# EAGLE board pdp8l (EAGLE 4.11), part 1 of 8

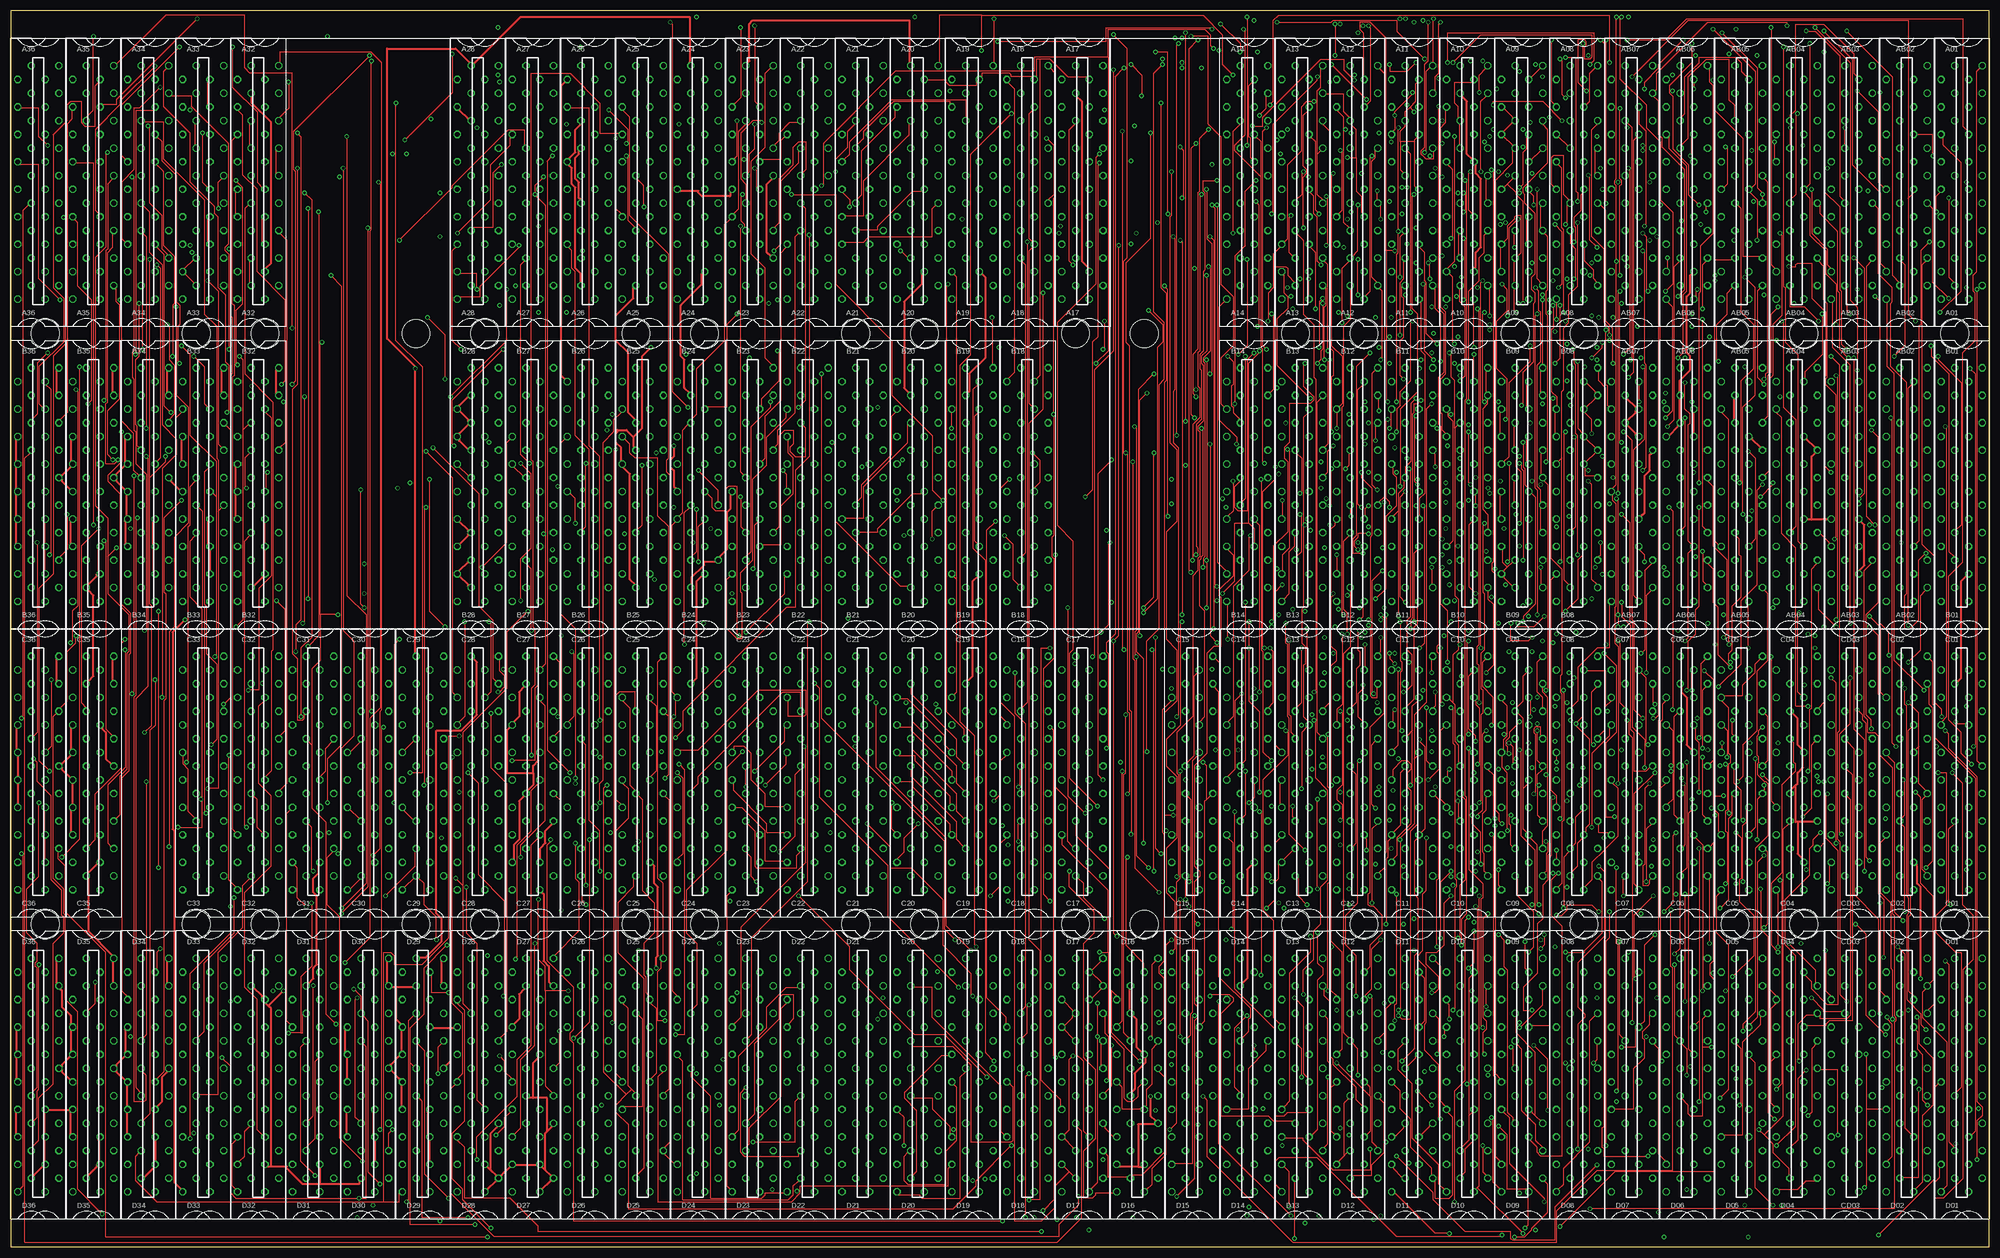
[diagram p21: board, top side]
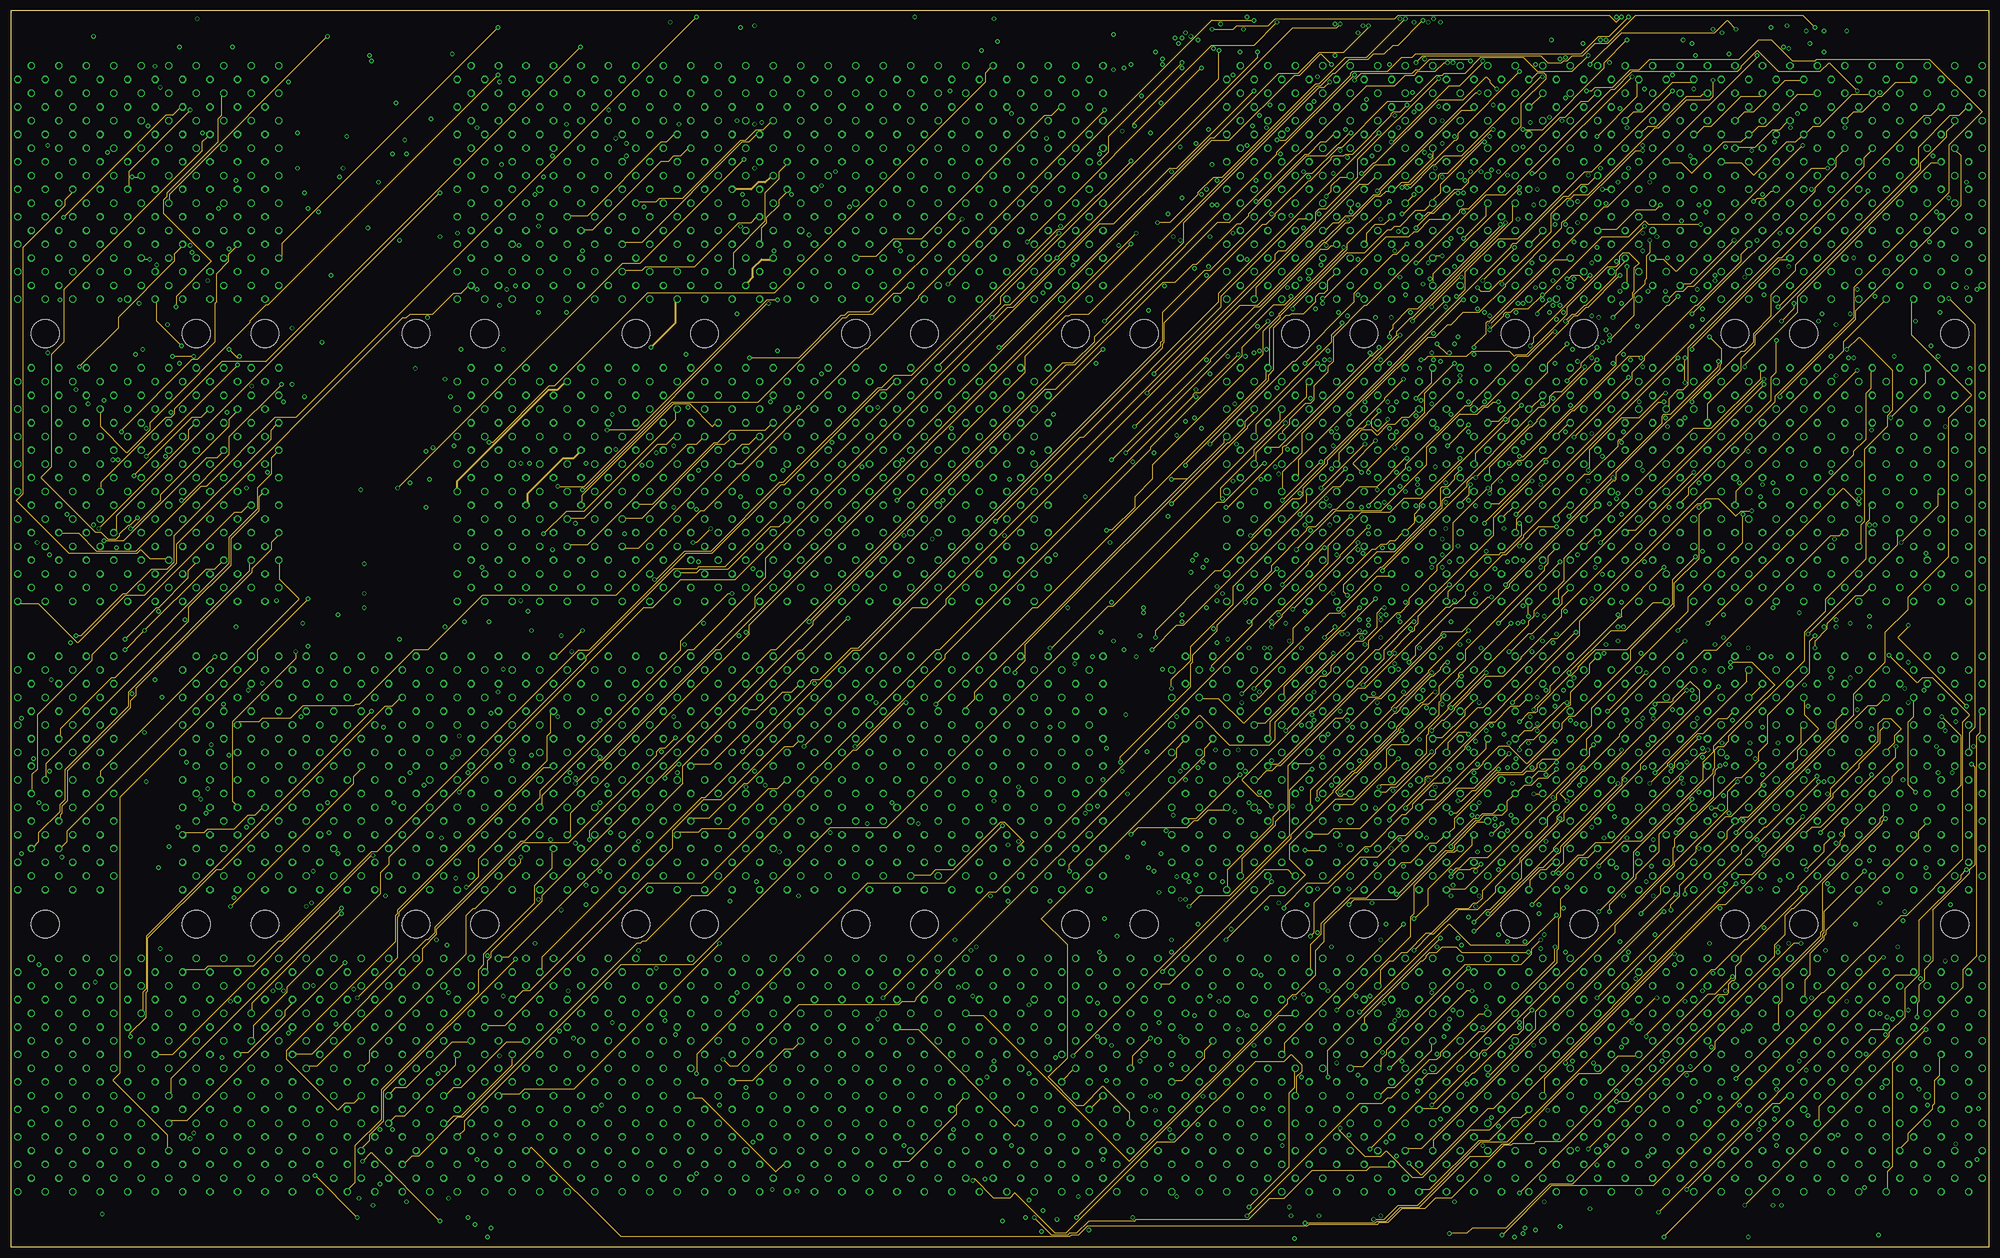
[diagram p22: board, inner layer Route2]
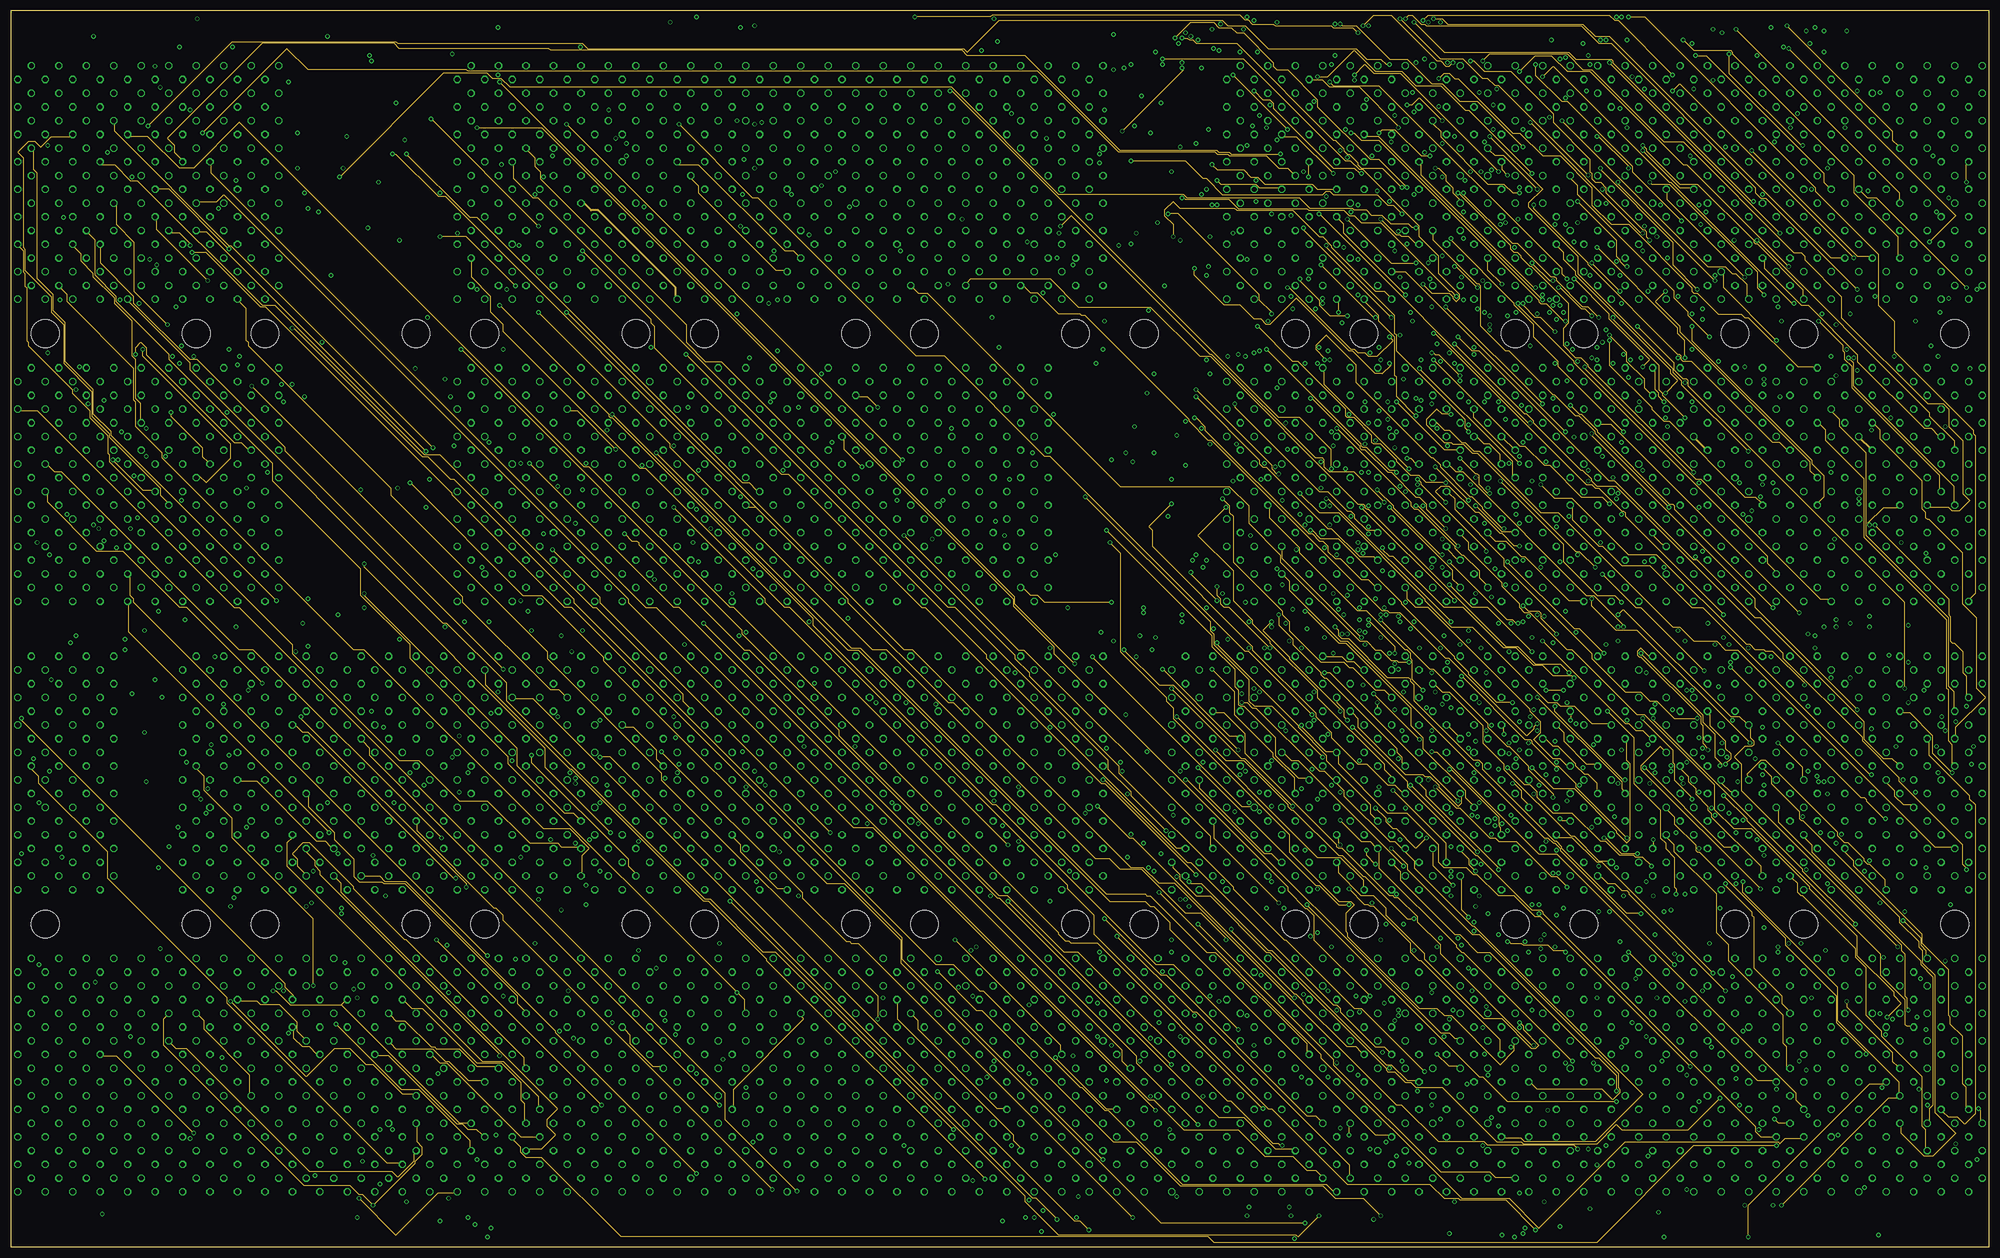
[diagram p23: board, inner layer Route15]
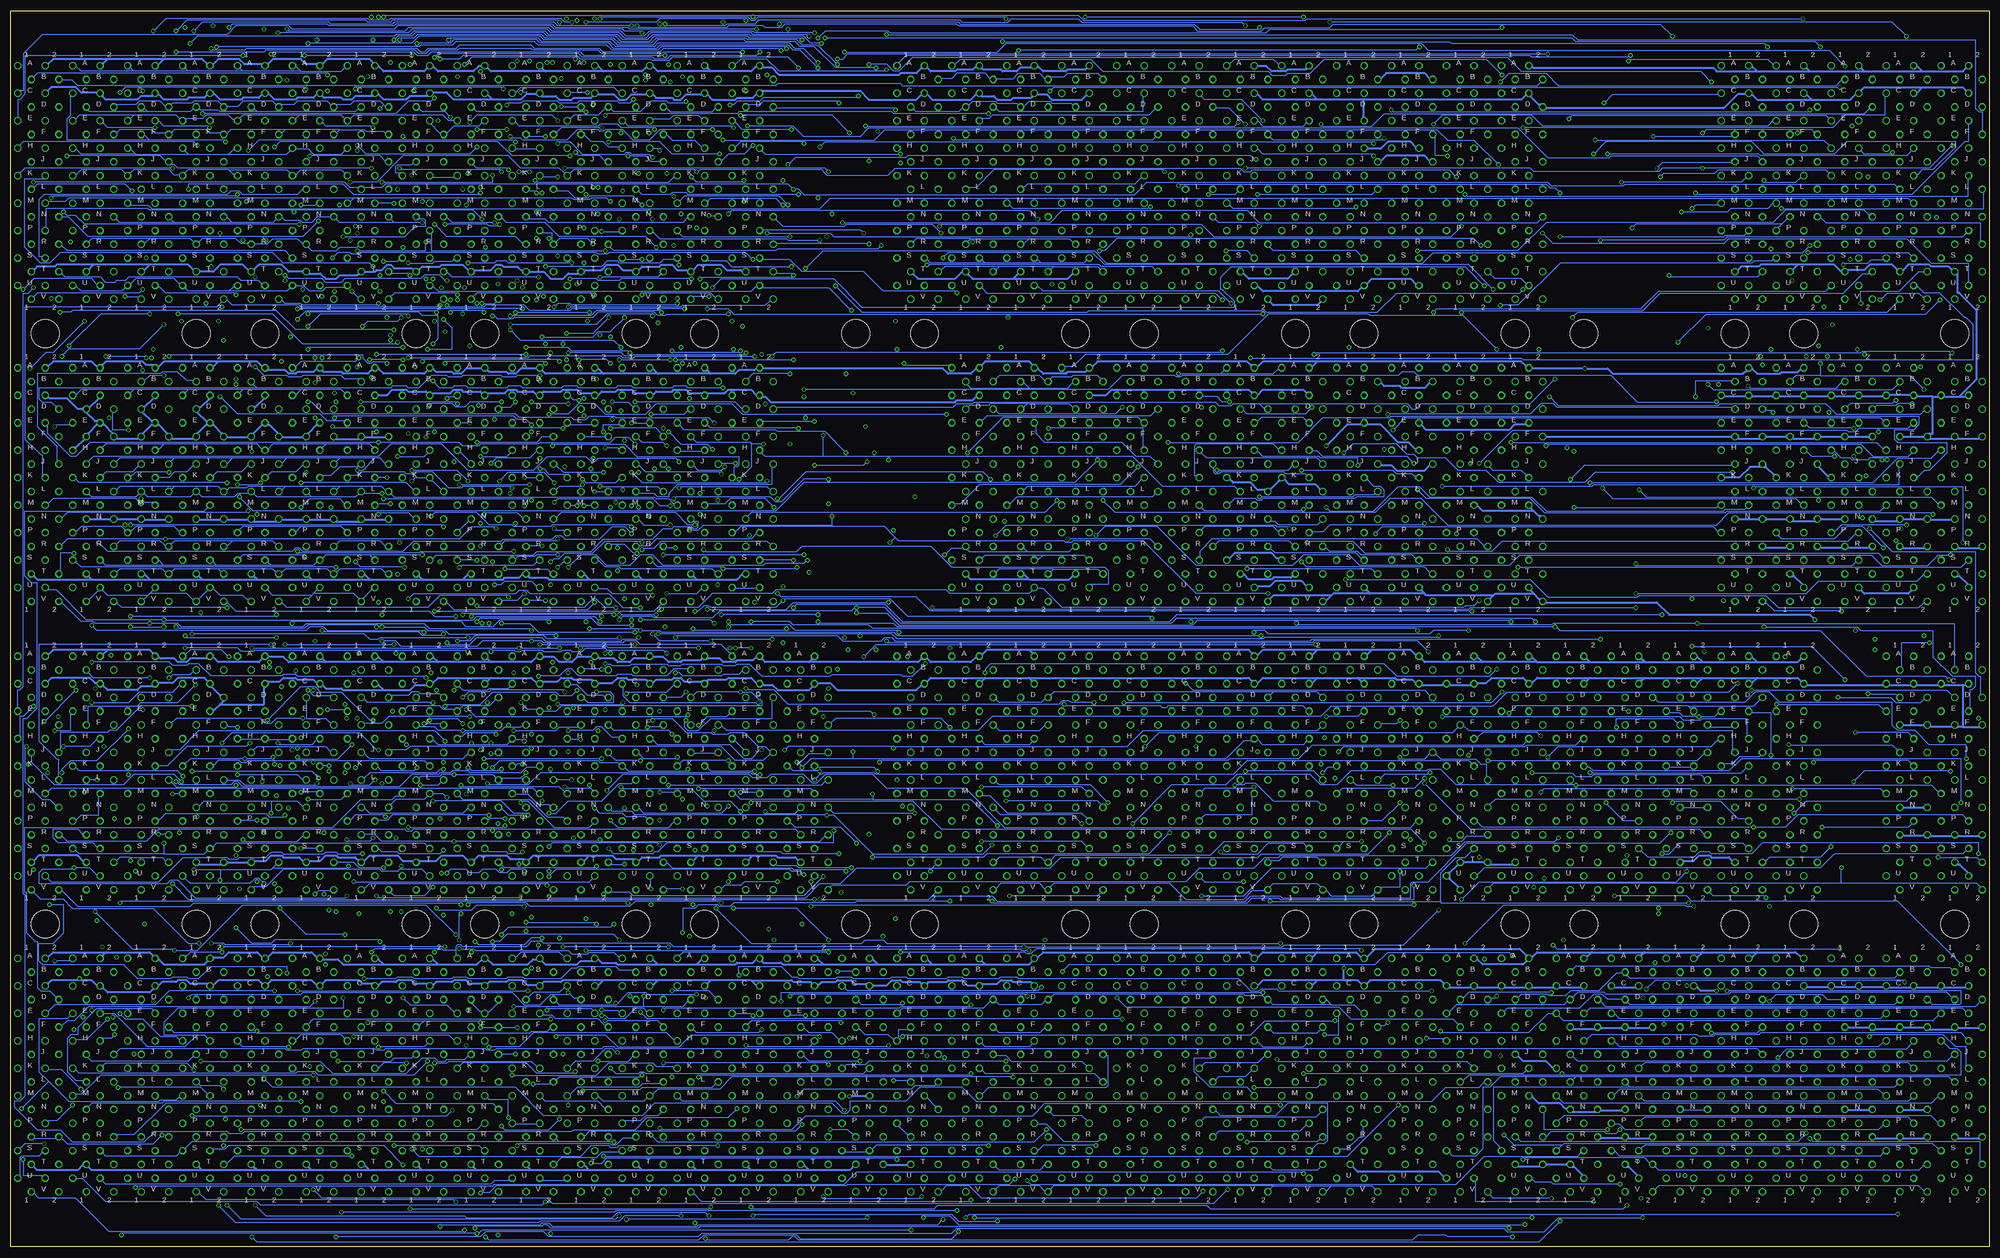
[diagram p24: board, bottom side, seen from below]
Size 457.2 x 285.75 mm. Coordinates in mm from the lower left corner, seen from the top.
Outline: 0,0 457.2,0 457.2,285.75 0,285.75 0,0
Copper layers (1*2*15*16): Top 0.035mm / dielectric 1.5mm / Route2 0.035mm / dielectric 0.15mm / Route15 0.035mm / dielectric 0.2mm / Bottom 0.035mm
Design rules "10mils": minimum track width 8mil, minimum drill 24mil, track to track 8mil, track to pad 8mil, pad to pad 8mil, via to via 8mil, smd to smd 8mil, copper to edge 25mil, drill to drill 8mil, minimum pad ring 8mil, minimum via ring 8mil, stop-mask expansion 0mil, vias tented up to drill 0mil, thermal gap 10mil
Net classes: 1 Supply: width 0.508 mm

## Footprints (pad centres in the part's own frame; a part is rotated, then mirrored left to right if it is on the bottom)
H807 = drill 1.092 octagon: A1 4.763,28.575; A2 -1.587,28.575; B1 1.587,25.4; B2 -4.763,25.4; C1 4.763,22.225; C2 -1.587,22.225; D1 1.587,19.05; D2 -4.763,19.05; E1 4.763,15.875; E2 -1.587,15.875; F1 1.587,12.7; F2 -4.763,12.7; H1 4.763,9.525; H2 -1.587,9.525; J1 1.587,6.35; J2 -4.763,6.35; K1 4.763,3.175; K2 -1.587,3.175; L1 1.587,0; L2 -4.763,0; M1 4.763,-3.175; M2 -1.587,-3.175; N1 1.587,-6.35; N2 -4.763,-6.35; P1 4.763,-9.525; P2 -1.587,-9.525; R1 1.587,-12.7; R2 -4.763,-12.7; S1 4.763,-15.875; S2 -1.587,-15.875; T1 1.587,-19.05; T2 -4.763,-19.05; U1 4.763,-22.225; U2 -1.587,-22.225; V1 1.587,-25.4; V2 -4.763,-25.4
H807-2 = drill 1.092 octagon: AA1 4.763,60.325; AA2 -1.587,60.325; AB1 1.587,57.15; AB2 -4.763,57.15; AC1 4.763,53.975; AC2 -1.587,53.975; AD1 1.587,50.8; AD2 -4.763,50.8; AE1 4.763,47.625; AE2 -1.587,47.625; AF1 1.587,44.45; AF2 -4.763,44.45; AH1 4.763,41.275; AH2 -1.587,41.275; AJ1 1.587,38.1; AJ2 -4.763,38.1; AK1 4.763,34.925; AK2 -1.587,34.925; AL1 1.587,31.75; AL2 -4.763,31.75; AM1 4.763,28.575; AM2 -1.587,28.575; AN1 1.587,25.4; AN2 -4.763,25.4; AP1 4.763,22.225; AP2 -1.587,22.225; AR1 1.587,19.05; AR2 -4.763,19.05; AS1 4.763,15.875; AS2 -1.587,15.875; AT1 1.587,12.7; AT2 -4.763,12.7; AU1 4.763,9.525; AU2 -1.587,9.525; AV1 1.587,6.35; AV2 -4.763,6.35; BA1 4.763,-9.525; BA2 -1.587,-9.525; BB1 1.587,-12.7; BB2 -4.763,-12.7; BC1 4.763,-15.875; BC2 -1.587,-15.875; BD1 1.587,-19.05; BD2 -4.763,-19.05; BE1 4.763,-22.225; BE2 -1.587,-22.225; BF1 1.587,-25.4; BF2 -4.763,-25.4; BH1 4.763,-28.575; BH2 -1.587,-28.575; BJ1 1.587,-31.75; BJ2 -4.763,-31.75; BK1 4.763,-34.925; BK2 -1.587,-34.925; BL1 1.587,-38.1; BL2 -4.763,-38.1; BM1 4.763,-41.275; BM2 -1.587,-41.275; BN1 1.587,-44.45; BN2 -4.763,-44.45; BP1 4.763,-47.625; BP2 -1.587,-47.625; BR1 1.587,-50.8; BR2 -4.763,-50.8; BS1 4.763,-53.975; BS2 -1.587,-53.975; BT1 1.587,-57.15; BT2 -4.763,-57.15; BU1 4.763,-60.325; BU2 -1.587,-60.325; BV1 1.587,-63.5; BV2 -4.763,-63.5
CBLOCK = hole 6.452: 7.938,68.263; 42.862,68.263

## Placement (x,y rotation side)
A01  G921  [H807]  450.85,244.47 0 top
A08  M617  [H807]  361.95,244.47 0 top
A09  M617  [H807]  349.25,244.47 0 top
A10  M160  [H807]  336.55,244.47 0 top
A11  M115  [H807]  323.85,244.47 0 top
A12  M160  [H807]  311.15,244.47 0 top
A13  M160  [H807]  298.45,244.47 0 top
A14  M115  [H807]  285.75,244.47 0 top
A17  G020  [H807]  247.65,244.47 0 top
A18  G020  [H807]  234.95,244.47 0 top
A19  G020  [H807]  222.25,244.47 0 top
A20  G020  [H807]  209.55,244.47 0 top
A21  W025A  [H807]  196.85,244.47 0 top
A22  W025A  [H807]  184.15,244.47 0 top
A23  G228  [H807]  171.45,244.47 0 top
A24  G228  [H807]  158.75,244.47 0 top
A25  G624  [H807]  146.05,244.47 0 top
A26  G624  [H807]  133.35,244.47 0 top
A27  G826A  [H807]  120.65,244.47 0 top
A28  G785A  [H807]  107.95,244.47 0 top
A32  M516  [H807]  57.15,244.47 0 top
A33  M516  [H807]  44.45,244.47 0 top
A34  M111  [H807]  31.75,244.47 0 top
A35  M111  [H807]  19.05,244.47 0 top
A36  M916  [H807]  6.35,244.47 0 top
AB02  M220  [H807-2]  438.15,212.72 0 top
AB03  M220  [H807-2]  425.45,212.72 0 top
AB04  M220  [H807-2]  412.75,212.72 0 top
AB05  M220  [H807-2]  400.05,212.72 0 top
AB06  M220  [H807-2]  387.35,212.72 0 top
AB07  M220  [H807-2]  374.65,212.72 0 top
B01  G921  [H807]  450.85,174.62 0 top
B08  M617  [H807]  361.95,174.62 0 top
B09  M617  [H807]  349.25,174.62 0 top
B10  M160  [H807]  336.55,174.62 0 top
B11  M216  [H807]  323.85,174.62 0 top
B12  M111  [H807]  311.15,174.62 0 top
B13  M113  [H807]  298.45,174.62 0 top
B14  M119  [H807]  285.75,174.62 0 top
B18  G020  [H807]  234.95,174.62 0 top
B19  G020  [H807]  222.25,174.62 0 top
B20  G020  [H807]  209.55,174.62 0 top
B21  W025B  [H807]  196.85,174.62 0 top
B22  W025B  [H807]  184.15,174.62 0 top
B23  G228  [H807]  171.45,174.62 0 top
B24  G228  [H807]  158.75,174.62 0 top
B25  G624  [H807]  146.05,174.62 0 top
B26  G624  [H807]  133.35,174.62 0 top
B27  G826B  [H807]  120.65,174.62 0 top
B28  G785B  [H807]  107.95,174.62 0 top
B32  M906  [H807]  57.15,174.62 0 top
B33  M906  [H807]  44.45,174.62 0 top
B34  M903  [H807]  31.75,174.62 0 top
B35  M903  [H807]  19.05,174.62 0 top
B36  M903  [H807]  6.35,174.62 0 top
C01  G921  [H807]  450.85,107.95 0 top
C02  M113  [H807]  438.15,107.95 0 top
C04  M216  [H807]  412.75,107.95 0 top
C05  M113  [H807]  400.05,107.95 0 top
C06  M216  [H807]  387.35,107.95 0 top
C07  M111  [H807]  374.65,107.95 0 top
C08  M216  [H807]  361.95,107.95 0 top
C09  M115  [H807]  349.25,107.95 0 top
C10  M119  [H807]  336.55,107.95 0 top
C11  M117  [H807]  323.85,107.95 0 top
C12  M115  [H807]  311.15,107.95 0 top
C13  M117  [H807]  298.45,107.95 0 top
C14  M113  [H807]  285.75,107.95 0 top
C15  M113  [H807]  273.05,107.95 0 top
C17  M360  [H807]  247.65,107.95 0 top
C18  G221  [H807]  234.95,107.95 0 top
C19  G221  [H807]  222.25,107.95 0 top
C20  G610A  [H807]  209.55,107.95 0 top
C21  H807  [H807]  196.85,107.95 0 top
C22  G610A  [H807]  184.15,107.95 0 top
C23  G221  [H807]  171.45,107.95 0 top
C24  G221  [H807]  158.75,107.95 0 top
C25  G228  [H807]  146.05,107.95 0 top
C26  M002  [H807]  133.35,107.95 0 top
C27  M623  [H807]  120.65,107.95 0 top
C28  M115  [H807]  107.95,107.95 0 top
C29  M660  [H807]  95.25,107.95 0 top
C30  M660  [H807]  82.55,107.95 0 top
C31  M916  [H807]  69.85,107.95 0 top
C32  M916  [H807]  57.15,107.95 0 top
C33  W023  [H807]  44.45,107.95 0 top
C35  M903  [H807]  19.05,107.95 0 top
C36  M903  [H807]  6.35,107.95 0 top
CD03  M700  [H807-2]  425.45,76.2 0 top
D01  G921  [H807]  450.85,38.1 0 top
D02  M111  [H807]  438.15,38.1 0 top
D04  M115  [H807]  412.75,38.1 0 top
D05  M310  [H807]  400.05,38.1 0 top
D06  M310  [H807]  387.35,38.1 0 top
D07  M310  [H807]  374.65,38.1 0 top
D08  M310  [H807]  361.95,38.1 0 top
D09  M160  [H807]  349.25,38.1 0 top
D10  M216  [H807]  336.55,38.1 0 top
D11  M113  [H807]  323.85,38.1 0 top
D12  M113  [H807]  311.15,38.1 0 top
D13  M111  [H807]  298.45,38.1 0 top
D14  M310  [H807]  285.75,38.1 0 top
D15  M310  [H807]  273.05,38.1 0 top
D16  M216  [H807]  260.35,38.1 0 top
D17  M617  [H807]  247.65,38.1 0 top
D18  G221  [H807]  234.95,38.1 0 top
D19  G221  [H807]  222.25,38.1 0 top
D20  G611B  [H807]  209.55,38.1 0 top
D21  H807  [H807]  196.85,38.1 0 top
D22  G611B  [H807]  184.15,38.1 0 top
D23  G221  [H807]  171.45,38.1 0 top
D24  G221  [H807]  158.75,38.1 0 top
D25  G228  [H807]  146.05,38.1 0 top
D26  H807  [H807]  133.35,38.1 0 top
D27  M623  [H807]  120.65,38.1 0 top
D28  M623  [H807]  107.95,38.1 0 top
D29  M906  [H807]  95.25,38.1 0 top
D30  M906  [H807]  82.55,38.1 0 top
D31  M916  [H807]  69.85,38.1 0 top
D32  M916  [H807]  57.15,38.1 0 top
D33  W076  [H807]  44.45,38.1 0 top
D34  M903  [H807]  31.75,38.1 0 top
D35  M903  [H807]  19.05,38.1 0 top
D36  M903  [H807]  6.35,38.1 0 top
U$1  [CBLOCK]  0,6.35 0 top
U$2  [CBLOCK]  50.8,6.35 0 top
U$3  [CBLOCK]  101.6,6.35 0 top
U$4  [CBLOCK]  152.4,6.35 0 top
U$5  [CBLOCK]  203.2,6.35 0 top
U$6  [CBLOCK]  254,6.35 0 top
U$7  [CBLOCK]  304.8,6.35 0 top
U$8  [CBLOCK]  355.6,6.35 0 top
U$9  [CBLOCK]  406.4,6.35 0 top
U$10  [CBLOCK]  0,142.88 0 top
U$11  [CBLOCK]  50.8,142.88 0 top
U$12  [CBLOCK]  101.6,142.88 0 top
U$13  [CBLOCK]  152.4,142.88 0 top
U$14  [CBLOCK]  203.2,142.88 0 top
U$15  [CBLOCK]  254,142.88 0 top
U$16  [CBLOCK]  304.8,142.88 0 top
U$17  [CBLOCK]  355.6,142.88 0 top
U$18  [CBLOCK]  406.4,142.88 0 top

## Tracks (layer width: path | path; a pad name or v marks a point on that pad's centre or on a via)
3CYCLE  (via drill 0.61)
  Route15 0.203: v309.27,25.86 309.27,27.89 D12.P2 | v217.83,27.08 176.78,68.12 173.94,68.12 161.75,80.31 160.53,80.31 114.61,126.24 114.61,130.3 100.79,144.12 99.97,144.12 41.45,202.64 41.45,204.27 27.23,218.49 A34.V2
  Bottom 0.203: v309.27,25.86 307.64,24.23 220.68,24.23 v217.83,27.08
(IOT+OPR)\  (via drill 0.61)
  Top 0.203: v319.84,52.27 319.84,55.93 320.24,56.34 v320.24,81.53 | v340.97,119.33 340.16,118.52 340.16,101.04 338.94,99.82 v338.94,99.42
  Route2 0.203: v320.24,81.53 320.65,81.53 338.12,99.01 338.94,99.01 340.16,100.23 342.6,100.23 343.81,101.45 C09.N2
  Bottom 0.203: v319.84,52.27 307.64,52.27 306.83,51.46 D12.F2 | v340.97,119.33 331.22,119.33 330.4,120.14 325.93,120.14 C11.F1 | v338.94,99.42 339.34,99.82 342.19,99.82 343.81,101.45 C09.N2
+3V(1)  (via drill 0.61)
  Top 0.203: C02.U1 442.57,86.41 441.76,87.22 441.76,103.48 442.57,104.29 C02.M1 442.57,105.51 440.94,107.14 440.94,115.67 | v438.51,125.83 440.94,123.39 440.94,115.67 | 440.94,115.67 440.13,114.86 C02.J1
  Bottom 0.203: v438.51,125.83 429.97,125.83 427.53,128.27 419.81,128.27 418.19,129.9 C04.C1
+3V(2)  (via drill 0.61)
  Top 0.203: v383.64,111.2 384.05,111.61 384.05,119.33 383.24,120.14 C06.F2
  Route15 0.203: C05.U1 404.37,86.41 404.37,88.04 392.99,99.42 392.99,100.23 392.18,101.04 392.18,101.85 389.33,104.7 389.33,105.92 387.71,107.54 387.71,108.76 386.08,110.39 C06.K2
  Bottom 0.203: v383.64,111.2 385.27,111.2 C06.K2 | C06.D1 388.93,126.24 388.93,122.17 384.45,122.17 383.24,120.95 C06.F2
+3V(3)  (via drill 0.61)
  Top 0.203: C08.D1 363.32,126.24 363.32,122.58 v361.7,120.95 361.7,120.55 364.95,117.3 364.95,97.79 364.13,96.98 364.13,95.76 C08.R1 363.32,94.54 362.1,93.32 362.1,88.04 360.48,86.41 C08.U2
  Route15 0.203: C08.K1 366.17,111.61 364.13,111.61 358.85,116.89 358.85,118.92 357.63,120.14 C08.F2
  Bottom 0.203: v361.7,120.95 357.63,120.95 C08.F2 | C05.V1 401.12,83.16 398.27,83.16 394.21,87.22 371.86,87.22 371.45,86.82 367.79,86.82 367.39,87.22 362.1,87.22 360.88,86 C08.U2
+3V(4)
  Top 0.203: D11.L2 319.43,37.64 321.06,36.02 321.06,31.95 323.49,29.52 323.49,23.01 328.37,18.14 328.37,16.51 D11.U1 329.18,15.29 329.18,11.23 332.44,11.23 333.25,12.04 333.25,29.92 332.03,31.14 D10.N2 331.62,32.36 330.4,33.58 330.4,64.87 329.18,66.09 D11.A1 | D10.R1 338.12,24.64 336.09,22.61 336.09,17.32 335.28,16.51 D10.U2
  Bottom 0.203: D11.A1 329.18,66.9 330.4,68.12 339.34,68.12 340.56,66.9 D10.A1 | D10.U2 334.47,15.29 329.18,15.29 D11.U1
+3V(5)
  Top 0.203: C10.F2 331.22,120.14 330.4,119.33 330.4,103.48 331.62,102.26 C10.N2 | C10.U1 340.97,86.41 340.56,86.82 340.56,90.88 340.16,91.29 340.16,100.23 340.97,101.04 340.97,104.29 C10.M1
  Route15 0.203: C10.H2 334.47,118.11 332.44,120.14 C10.F2
  Bottom 0.203: C10.N2 332.44,101.85 332.84,102.26 335.28,102.26 337.72,104.7 340.56,104.7 C10.M1
+3V(6)  (via drill 0.61)
  Top 0.203: v352.75,244.5 352.75,223.77 353.57,222.96 A09.U1 | A10.H2 334.87,254.66 334.87,259.54 A10.E2 334.47,260.76 334.47,263.6 333.65,264.41 333.65,269.29 337.72,269.29 A10.B1
  Route15 0.203: v352.75,244.5 345.03,252.22 343,252.22 341.78,253.44 A10.H1
  Bottom 0.203: A10.H2 335.69,253.85 340.56,253.85 A10.H1
+3V(7)  (via drill 0.61)
  Top 0.203: B10.R2 332.44,162.41 333.25,163.22 333.25,190.86 332.03,192.07 332.03,192.89 B10.D2 | v353.57,157.12 353.57,153.06 B09.U1
  Route15 0.203: B10.S2 334.47,159.16 334.06,159.16 332.03,161.19 B10.R2
  Bottom 0.203: v353.57,157.12 353.16,157.53 336.5,157.53 335.69,158.34 B10.S2
+3V(8)
  Top 0.203: 352.35,30.33 351.54,31.14 351.54,31.55 D09.N1 | 352.35,30.33 353.57,29.11 D09.P1 | 352.35,30.33 352.35,44.96 347.88,49.43 347.88,53.49 D09.E2
  Route2 0.203: D11.V1 325.93,13.26 327.96,13.26 339.34,24.64 341.78,24.64 347.07,29.92 349.1,29.92 350.32,31.14 D09.N1
  Bottom 0.203: D09.D2 344.63,56.34 346.66,54.3 347.07,54.3 D09.E2 348.29,54.3 348.69,54.3 350.72,56.34 D09.D1
+3V(9)  (via drill 0.61)
  Top 0.203: v307.24,253.44 307.64,253.03 307.64,239.62 306.83,238.81 A12.N2
  Route15 0.203: v322.27,220.12 308.05,234.34 308.05,236.37 306.83,237.59 A12.N2
  Bottom 0.203: v307.24,253.44 307.64,253.85 308.86,253.85 A12.H2 | v322.27,220.12 322.68,220.52 349.5,220.52 350.32,219.71 A09.V1
+3V(10)  (via drill 0.61)
  Top 0.203: v364.54,177.04 365.35,176.22 365.35,154.28 366.57,153.06 B08.U1
  Bottom 0.203: v364.54,177.04 363.73,177.85 360.88,177.85 B08.K2 360.07,177.04 359.66,177.04 357.63,175.01 B08.L2
+3V(11)  (via drill 0.61)
  Top 0.203: 320.65,170.13 319.43,168.91 B11.N2 | 320.65,170.13 320.65,174.19 321.87,175.41 321.87,177.04 B11.K2 322.27,178.26 322.27,180.29 323.49,181.51 323.49,194.92 v324.71,196.14 | 320.65,170.13 v320.65,145.75
  Route2 0.203: v324.71,196.14 328.37,199.8 328.37,202.64 B11.A1 | v350.72,145.75 350.72,148.59 B09.V1
  Bottom 0.203: v350.72,145.75 350.32,146.15 321.06,146.15 v320.65,145.75
+3V(12)
  Top 0.203: B10.P1 341.38,165.66 341.38,169.32 340.16,170.54 340.16,193.7 341.38,194.92 341.38,196.14 B10.C1 340.97,197.36 340.97,202.64 B10.A1
  Route15 0.203: B08.V1 362.92,149.4 360.07,149.4 349.91,159.56 349.1,159.56 345.44,163.22 343,163.22 341.78,164.44 B10.P1
+3V(13)  (via drill 0.61)
  Top 0.203: v251.16,56.34 v251.16,48.62 251.16,14.88 249.53,13.26 D17.V1 | C25.A1 150.37,135.99 149.56,135.18 149.56,85.19 150.77,83.97 150.77,67.31 D25.A1 150.37,66.09 150.37,64.47 149.56,63.65 149.56,52.27 v151.18,52.27
  Bottom 0.203: v251.16,56.34 251.56,55.93 260.5,55.93 261.31,56.74 D16.D1 | v251.16,48.62 250.75,49.02 170.69,49.02 167.44,52.27 v151.18,52.27
+3V(15)
  Top 0.203: D31.S2 68.28,23.01 70.31,25.04 70.31,42.93 71.12,43.74 D31.J1 | C31.N2 64.62,101.04 63.8,100.23 63.8,52.27 64.62,51.46 D31.F2
  Route15 0.203: D31.F2 65.43,50.24 65.43,48.21 67.46,46.18 69.09,46.18 70.71,44.55 D31.J1
  Bottom 0.203: C31.N2 65.84,101.45 70.71,101.45 C31.N1
+3V(16)
  Top 0.203: D32.R1 58.12,25.86 56.9,27.08 56.9,57.15 54.05,60 54.05,81.94 60.15,88.04 60.15,104.29 57.3,107.14 57.3,125.02 58.52,126.24 C32.D1
+3V(17)
  Bottom 0.203: B14.U2 284.89,152.25 289.76,152.25 B14.U1
+3V(18)
  Top 0.203: A08.U1 366.57,222.96 365.76,223.77 365.76,225.81 363.73,227.84 363.73,231.09 A08.R1
-15V
  Top 0.203: A18.B2 230.43,269.29 232.05,267.67 232.05,202.23 230.43,200.61 B18.B2
  Route2 0.203: D33.B2 40.23,64.06 44.7,64.06 45.52,64.87 56.08,64.87 61.77,70.56 62.59,70.56 83.31,91.29 84.53,91.29 131.27,138.02 133.71,138.02 156.06,160.38 162.15,160.38 178,176.22 178.82,176.22 200.76,198.17 202.39,198.17 204.01,199.8 B20.B2
  Bottom 0.203: A20.B2 205.23,270.51 206.04,271.32 212.95,271.32 213.77,270.51 217.02,270.51 A19.B2 218.24,270.1 219.46,271.32 224.33,271.32 225.55,270.1 229.62,270.1 A18.B2 230.84,270.1 232.05,271.32 238.56,271.32 239.78,270.1 242.21,270.1 A17.B2 | B18.B2 229.62,200.61 228.8,201.42 219.46,201.42 218.24,200.2 B19.B2 217.02,200.61 216.61,201.02 212.14,201.02 211.73,201.42 206.04,201.42 205.23,200.61 B20.B2
A01B2
  Bottom 0.203: A28.B2 103.63,269.29 104.44,268.48 251.16,268.48 251.56,268.88 280.01,268.88 280.42,268.48 441.76,268.48 442.98,269.7 445.41,269.7 A01.B2
A01V1  (via drill 0.61)
  Route2 0.203: v264.97,236.78 267.82,236.78 274.32,243.28 274.32,243.69 277.98,247.34 280.01,247.34 301.55,268.88 302.36,268.88 308.46,274.98 313.33,274.98 v322.27,283.92
  Route15 0.203: v322.27,283.92 323.09,284.73 323.9,284.73 325.93,282.7 326.75,282.7 327.15,282.3 362.92,282.3 366.98,278.23 369.82,278.23 403.15,244.91 403.15,243.69 404.37,242.47 405.59,242.47 v426.72,221.34
  Bottom 0.203: v264.97,236.78 217.02,236.78 214.17,239.62 171.5,239.62 168.66,236.78 104.44,236.78 103.63,237.59 A28.N2 | v426.72,221.34 427.53,220.52 451.1,220.52 451.92,219.71 A01.V1
AC00  (via drill 0.61)
  Top 0.203: v130.45,93.32 130.45,85.19 131.27,84.38 131.27,73 125.58,67.31 D27.A1 | v286.11,102.67 287.32,103.89 287.32,107.14 C14.L1
  Route2 0.203: v382.02,195.33 380.8,195.33 372.26,186.79 371.86,186.79 371.45,186.38 371.45,185.17 364.95,178.66 363.73,178.66 349.5,164.44 349.5,164.03 345.44,159.97 344.63,159.97 336.09,151.44 336.09,150.62 334.06,148.59 333.25,148.59 332.44,147.78 331.62,147.78 312.93,129.08 311.3,129.08 293.42,111.2 292.61,111.2 291.39,109.98 290.17,109.98 288.14,107.95 C14.L1
  Route15 0.203: v382.02,195.33 380.8,196.54 380.8,197.36 379.98,198.17 379.98,202.64 AB07.BA1
  Bottom 0.203: v130.45,93.32 133.71,96.57 242.21,96.57 248.72,103.07 285.7,103.07 v286.11,102.67
AC00\  (via drill 0.61)
  Top 0.203: v301.95,204.27 302.77,205.08 302.77,207.11 303.17,207.52 v303.17,218.08 | v376.33,195.33 376.33,199.39 AB07.BB1
  Route2 0.203: v301.95,204.27 287.73,190.04 287.73,188.01 B14.F1 | v400.71,203.45 400.71,203.86 412.9,216.05 412.9,219.71 443.79,250.6 445.41,250.6 A01.J2
  Route15 0.203: v331.62,217.27 v353.97,194.92
  Bottom 0.203: v303.17,218.08 303.58,217.68 327.56,217.68 327.96,218.08 330.81,218.08 v331.62,217.27 | v353.97,194.92 354.38,195.33 v376.33,195.33 | v400.71,203.45 398.68,201.42 393.39,201.42 392.99,201.02 390.14,201.02 389.74,201.42 380.8,201.42 379.98,200.61 376.73,200.61 AB07.BB1
AC01  (via drill 0.61)
  Top 0.203: v377.14,234.34 377.95,233.53 377.95,221.34 v378.36,220.93
  Route2 0.203: v322.68,264.01 321.06,262.38 319.43,262.38 319.02,261.98 319.02,261.57 310.08,252.63 308.46,252.63 308.05,252.22 305.61,252.22 305.21,251.82 305.21,251.41 300.33,246.53 299.92,246.53 292.2,238.81 292.2,238.4 290.17,236.37 289.36,236.37 266.6,213.61 266.6,209.14 266.19,208.74 266.19,207.92 196.29,138.02 194.67,138.02 160.53,103.89 159.72,103.89 122.73,66.9 122.73,64.06 D27.B1
  Route15 0.203: v322.68,264.01 323.9,264.01 325.53,265.63 v330.81,260.35 | v351.13,259.94 376.73,234.34 v377.14,234.34
  Bottom 0.203: v330.81,260.35 332.03,261.57 349.5,261.57 v351.13,259.94 | v378.36,220.93 377.14,219.71 376.73,219.71 AB07.AV1
AC01\  (via drill 0.61)
  Top 0.203: v445.01,239.22 445.01,242.88 445.82,243.69 A01.L2
  Route2 0.203: v316.18,207.92 316.18,207.52 314.55,205.89 314.15,205.89 293.01,184.76 290.98,184.76 B14.H1 | v341.78,211.99 345.03,215.24 345.03,215.65 345.44,216.05 346.66,216.05 347.47,216.86 350.72,216.86 v353.97,220.12 354.38,220.12 367.79,233.53 373.89,233.53 377.55,237.19 378.36,236.37 v390.55,236.37
  Bottom 0.203: v316.18,207.92 317.81,209.55 339.34,209.55 v341.78,211.99 | v353.97,220.12 354.38,220.52 368.61,220.52 369.42,219.71 AB07.AV2 | v445.01,239.22 444.19,238.4 442.16,238.4 440.13,236.37 v390.55,236.37
AC02  (via drill 0.61)
  Route2 0.203: v201.57,57.56 225.96,81.94 227.58,81.94 292.61,146.96 293.42,146.96 304.39,157.94 304.39,162 312.12,169.72 318.62,169.72 321.87,172.97 325.93,172.97 334.87,181.91 v334.87,182.32 | v341.78,174.19 341.78,174.6 342.19,175.01 342.19,176.22 346.25,180.29 346.66,180.29 348.29,181.91 349.5,181.91 360.88,193.29 361.29,193.29 373.89,205.89 376.33,205.89 v376.73,205.49
  Route15 0.203: v334.87,182.32 338.53,178.66 338.94,178.66 339.34,178.26 339.34,176.22 341.38,174.19 v341.78,174.19
  Bottom 0.203: v201.57,57.56 199.54,55.52 150.37,55.52 147.52,52.68 123.95,52.68 122.73,51.46 D27.F1 | v376.73,205.49 377.55,204.67 390.14,204.67 391.36,203.45 AB06.BA1
AC02\  (via drill 0.61)
  Top 0.203: v388.52,195.33 388.52,199.39 AB06.BB1
  Route2 0.203: v294.64,190.45 287.73,183.54 287.73,181.51 B14.J1 | v429.16,244.09 429.16,243.69 412.5,227.03 412.5,225.81 406.81,220.12 406.81,215.24 402.74,211.18 402.74,209.14 400.71,207.11 399.9,207.11 388.52,195.73 v388.52,195.33
  Bottom 0.203: v294.64,190.45 295.86,191.67 317.4,191.67 317.81,192.07 323.49,192.07 324.31,191.26 327.15,191.26 327.56,191.67 339.75,191.67 340.56,192.48 384.86,192.48 387.71,195.33 v388.52,195.33 | v429.16,244.09 430.78,245.72 451.1,245.72 451.92,244.91 A01.L1
AC03  (via drill 0.61)
  Top 0.203: v130.05,48.21 133.71,51.87 v133.71,94.13 | v389.74,221.34 389.33,220.93 389.33,219.71 AB06.AV1
  Route2 0.203: v133.71,94.13 133.71,96.16 175.56,138.02 176.78,138.02 243.03,204.27 245.47,204.27 250.34,209.14 250.34,210.36 292.61,252.63 292.61,253.03 v310.49,270.92
  Route15 0.203: v310.49,270.92 312.93,273.36 314.96,271.32 321.06,271.32 v343.81,248.56 | v367.39,249.38 367.39,248.97 384.05,232.31 384.05,227.03 v389.74,221.34
  Bottom 0.203: v130.05,48.21 125.98,48.21 D27.H1 | v343.81,248.56 344.22,248.97 366.98,248.97 v367.39,249.38
AC03\  (via drill 0.61)
  Top 0.203: v382.42,191.67 384.05,193.29 384.05,217.27 382.83,218.49 AB06.AV2
  Route2 0.203: v332.03,185.17 v336.91,190.04 | v419.81,249.38 416.15,249.38 388.93,222.15 387.71,222.15 386.49,220.93 384.86,220.93 383.24,219.3 AB06.AV2
  Bottom 0.203: v332.03,185.17 331.62,185.57 315.37,185.57 312.52,182.73 288.95,182.73 288.95,180.7 289.36,180.29 290.17,180.29 290.17,178.26 B14.K1 | v336.91,190.04 338.12,191.26 340.16,191.26 340.97,192.07 382.02,192.07 v382.42,191.67 | v419.81,249.38 453.95,249.38 455.17,248.16 A01.K1
AC04  (via drill 0.61)
  Top 0.203: 123.55,59.18 123.55,64.87 121.92,66.5 v121.92,80.31 | 123.55,59.18 123.55,37.24 125.17,35.61 D27.M1 | v69.9,86.82 69.49,87.22 69.49,96.98 68.68,97.79 C31.P2 | v288.54,100.63 288.95,100.23 v288.95,62.84 | v128.83,59.18 123.55,59.18
  Route2 0.203: v316.18,106.32 316.59,106.73 319.84,106.73 327.15,114.05 327.15,118.11 327.56,118.52 327.56,119.74 332.03,124.21 332.03,125.02 350.72,143.71 350.72,144.53 351.94,145.75 351.94,146.96 358.85,153.87 358.85,159.16 388.93,189.23 392.99,189.23 404.37,200.61 404.37,202.64 AB05.BA1
  Bottom 0.203: v121.92,80.31 117.86,84.38 72.34,84.38 v69.9,86.82 | v316.18,106.32 315.77,105.92 299.92,105.92 297.08,103.07 290.98,103.07 v288.54,100.63 | v288.95,62.84 288.95,64.87 279.2,64.87 276.76,62.43 275.54,62.43 275.13,62.03 266.6,62.03 266.19,62.43 262.94,62.43 262.53,62.03 254,62.03 253.59,62.43 250.34,62.43 249.94,62.03 241,62.03 240.59,62.43 237.34,62.43 236.93,62.03 228.8,62.03 228.4,62.43 224.74,62.43 224.33,62.03 173.53,62.03 170.69,59.18 168.66,59.18 168.25,59.59 164.59,59.59 164.19,59.18 v128.83,59.18
AC04\  (via drill 0.61)
  Top 0.203: v287.32,206.7 285.7,205.08 285.7,170.13 283.67,170.13 282.85,170.94 282.85,175.82 284.07,177.04 B14.K2
  Route15 0.203: v328.37,206.7 328.78,206.7 329.18,206.3 330,206.3 v334.87,201.42
  Bottom 0.203: v287.32,206.7 287.73,206.3 313.33,206.3 313.74,205.89 315.37,205.89 316.18,206.7 v328.37,206.7 | v334.87,201.42 340.16,201.42 340.56,201.02 343.41,201.02 343.81,201.42 352.75,201.42 353.16,201.02 356.01,201.02 356.41,201.42 360.07,201.42 362.92,198.58 365.35,198.58 365.76,198.98 369.01,198.98 369.42,198.58 400.3,198.58 | 400.3,198.58 401.12,199.39 AB05.BB1 | 400.3,198.58 450.7,198.58 450.7,196.14 449.88,195.33 447.85,195.33 446.63,194.11 B01.D2
AC05  (via drill 0.61)
  Top 0.203: v358.44,260.35 353.97,264.82 342.6,264.82 v342.6,264.01 | v305.21,273.36 v313.33,265.23
  Route2 0.203: v305.21,273.36 302.77,275.79 297.89,270.92 296.67,270.92 281.63,255.88 277.57,255.88 171.91,150.22 171.91,147.78 136.55,112.42 135.74,112.42 v130.45,107.14
  Route15 0.203: D27.N1 121.92,32.36 121.92,34.8 113.79,42.93 108.92,42.93 63.8,88.04 63.8,93.32 65.02,94.54 C31.R2 | v358.44,260.35 392.18,226.62 396.24,226.62 397.87,224.99 398.68,224.99 401.12,222.56 401.12,219.71 AB05.AV1
  Bottom 0.203: v342.6,264.01 342.19,264.41 339.34,264.41 338.94,264.82 330.81,264.82 330.4,264.41 326.34,264.41 325.93,264.82 316.99,264.82 316.59,264.41 314.15,264.41 v313.33,265.23 | v130.45,107.14 119.89,96.57 67.06,96.57 65.84,95.35 C31.R2
AC05\  (via drill 0.61)
  Top 0.203: v372.26,218.08 371.86,217.68 371.86,186.38 v372.26,185.98
  Route2 0.203: v312.93,185.57 v302.77,175.41
  Bottom 0.203: v302.77,175.41 302.36,175.82 282.45,175.82 281.63,175.01 B14.L2 | v312.93,185.57 314.55,187.2 317.4,187.2 318.62,185.98 334.87,185.98 335.28,185.57 348.69,185.57 349.1,185.17 352.75,185.17 353.57,185.98 v372.26,185.98 438.91,185.98 442.16,182.73 443.38,182.73 448.67,188.01 448.67,190.04 B01.E2 | v372.26,218.08 372.67,217.68 389.74,217.68 390.14,218.08 393.8,218.08 394.61,218.9 AB05.AV2
AC06  (via drill 0.61)
  Top 0.203: v105.66,109.58 108.1,107.14 108.1,86 114.2,79.91 114.2,58.37 v113.79,57.96
  Route2 0.203: v330,270.1 311.3,251.41 311.3,247.34 303.99,240.03 302.36,240.03 301.55,239.22 301.55,237.19 294.64,230.28 293.01,230.28 292.2,229.46 292.2,228.24 211.73,147.78 208.48,147.78 164.19,103.48 160.12,103.48 152.81,96.16 152.81,92.1 119.89,59.18 118.26,59.18 116.64,57.56 D27.D2
  Route15 0.203: v330,270.1 331.22,271.32 332.44,271.32 333.65,270.1 334.47,270.1 347.07,257.5 348.69,257.5 353.97,252.22 358.04,252.22 365.35,244.91 365.35,240.84 369.82,236.37 373.89,236.37 388.52,221.74 388.52,220.93 388.93,220.52 389.74,220.52 394.61,215.65 399.9,215.65 400.71,214.83 401.52,214.83 412.9,203.45 416.97,203.45 AB04.BA1
  Bottom 0.203: v105.66,109.58 96.32,109.58 95.5,108.76 91.85,108.76 91.44,109.17 66.65,109.17 65.84,108.36 C31.L2 | v113.79,57.96 114.2,57.56 115.42,57.56 D27.D2
AC06\  (via drill 0.61)
  Top 0.203: v285.29,205.89 285.29,172.97 284.48,172.16 B14.M2 | v365.35,205.49 367.79,207.92 v367.79,209.14 | v418.59,215.65 418.59,206.3 414.53,202.23 414.53,200.61 AB04.BB1
  Bottom 0.203: v285.29,205.89 312.93,205.89 313.33,205.49 315.77,205.49 316.18,205.89 337.31,205.89 337.72,205.49 v365.35,205.49 | v367.79,209.14 368.2,208.74 389.74,208.74 396.65,215.65 v418.59,215.65 | B01.J2 446.63,181.51 446.63,185.17 451.1,189.64 451.1,201.83 422.66,201.83 422.25,202.23 418.59,202.23 416.56,200.2 414.93,200.2 AB04.BB1
AC07  (via drill 0.61)
  Route2 0.203: v307.24,282.7 306.43,281.89 296.27,281.89 231.65,217.27 230.43,217.27 167.44,154.28 154.84,154.28 148.34,147.78 146.3,147.78 v103.63,105.1
  Route15 0.203: C31.M2 68.68,104.29 68.68,101.85 74.78,95.76 74.78,94.13 79.25,89.66 79.25,85.6 80.47,84.38 85.75,84.38 86.16,83.97 91.03,83.97 117.04,57.96 117.04,56.34 118.67,54.71 D27.E2 | v377.14,254.66 377.95,253.85 377.95,253.44 385.67,245.72 389.74,245.72 402.74,232.72 402.74,232.31 403.15,231.9 403.56,231.9 414.12,221.34 414.12,219.71 AB04.AV1 | v349.5,254.25 338.94,264.82 334.87,264.82 330.81,268.88 328.37,268.88 322.68,274.57 318.62,274.57 310.9,282.3 307.64,282.3 v307.24,282.7
  Bottom 0.203: v377.14,254.66 375.11,252.63 351.13,252.63 v349.5,254.25 | v103.63,105.1 102.82,105.92 69.09,105.92 68.68,105.51 C31.M2
AC07\  (via drill 0.61)
  Top 0.203: v282.45,177.04 282.45,170.13 281.23,168.91 B14.N2 | v356.82,204.27 358.04,205.49 v358.04,217.68
  Route2 0.203: v313.74,179.07 313.33,179.48 326.75,192.89 326.75,197.36 v333.65,204.27
  Bottom 0.203: v282.45,177.04 282.85,176.63 311.3,176.63 v313.74,179.07 | v333.65,204.27 334.06,204.67 356.41,204.67 v356.82,204.27 | v358.04,217.68 358.44,217.27 390.14,217.27 390.55,217.68 405.99,217.68 407.21,218.9 AB04.AV2 408.43,218.49 409.65,217.27 453.95,217.27 453.95,186.79 450.29,183.13 449.88,183.13 449.88,178.26 B01.K2
AC08  (via drill 0.61)
  Route2 0.203: v385.27,142.49 425.91,183.13 425.91,183.95 428.75,186.79 428.75,197.36 429.97,198.58 429.97,202.64 AB03.BA1 | v317.4,147.78 316.99,147.78 315.77,146.56 315.77,143.31 312.52,140.06 310.9,140.06 305.21,134.37 305.21,133.15 303.99,131.93 302.77,131.93 292.2,121.36 292.2,117.3 290.98,116.08 281.63,116.08 274.73,122.99 209.3,57.56 209.3,57.15 208.89,56.74 206.04,56.74 205.23,55.93 182.07,55.93 167.84,41.71 166.22,41.71 v164.59,43.33
  Route15 0.203: D27.K2 118.67,41.71 118.67,43.74 91.44,70.97 91.03,70.97 79.25,82.75 79.25,83.16 69.09,93.32 67.46,93.32 65.02,90.88 66.24,89.66 66.24,88.04 67.87,86.41 C31.U2 | v357.23,141.68 353.57,145.34 353.57,146.56 353.16,146.96 350.72,146.96 v349.5,148.18
  Bottom 0.203: v385.27,142.49 384.86,142.09 362.92,142.09 362.1,141.28 357.63,141.28 v357.23,141.68 | v349.5,148.18 349.1,147.78 324.71,147.78 322.68,149.81 321.87,149.81 319.84,147.78 v317.4,147.78 | v164.59,43.33 164.19,42.93 120.7,42.93 119.48,41.71 D27.K2
AC08\  (via drill 0.61)
  Top 0.203: v321.46,119.33 321.06,119.74 321.06,132.74 321.46,133.15 321.46,135.18 321.06,135.59 v321.06,144.53 | v421.84,201.42 422.25,201.02 422.25,145.34 v421.84,144.93
  Route2 0.203: v321.46,119.33 v307.24,105.1
  Bottom 0.203: v307.24,105.1 303.99,105.1 C13.M1 | v321.06,144.53 322.27,145.75 349.5,145.75 350.32,144.93 v421.84,144.93 439.73,144.93 446.63,151.84 448.67,151.84 B01.U2 | v421.84,201.42 425.09,201.42 426.31,200.2 AB03.BB1
AC09  (via drill 0.61)
  Top 0.203: v112.98,44.15 114.2,42.93 114.2,40.49 115.82,38.86 D27.L2 | v430.78,219.71 432,218.49 432,144.12 434.04,142.09 v434.04,136.8
  Route2 0.203: v434.04,136.8 440.54,130.3 441.76,131.52 444.19,131.52 452.73,122.99 451.1,121.36 451.1,89.66 438.1,76.66 436.88,76.66 419,58.78 418.59,58.78 v398.68,38.86
  Route15 0.203: v112.98,44.15 112.98,44.55 71.53,86 71.53,86.82 70.31,88.04 70.31,89.26 68.28,91.29 C31.S2
  Bottom 0.203: v430.78,219.71 427.53,219.71 AB03.AV1 | v398.68,38.86 396.65,36.83 340.56,36.83 334.06,30.33 311.3,30.33 308.46,33.17 267.41,33.17 264.97,30.73 264.16,30.73 263.35,31.55 263.35,33.58 250.34,33.58 247.09,36.83 237.34,36.83 234.09,33.58 128.83,33.58 125.58,36.83 117.86,36.83 116.64,38.05 D27.L2
AC09\  (via drill 0.61)
  Top 0.203: v425.09,144.12 425.09,203.86 421.03,207.92 421.03,218.49 AB03.AV2
  Route2 0.203: v336.91,142.49 327.56,133.15 327.56,132.74 322.27,127.46 321.87,127.46 319.02,124.61 319.02,124.21 300.33,105.51 300.33,102.26 C13.N1
  Bottom 0.203: v336.91,142.49 337.31,142.9 360.48,142.9 361.7,144.12 388.93,144.12 389.74,143.31 417.78,143.31 418.59,144.12 v425.09,144.12 437.69,144.12 438.1,144.53 440.94,144.53 445.41,149 B01.V2
AC10  (via drill 0.61)
  Top 0.203: v121.11,70.16 121.11,46.58 117.86,43.33 117.86,27.48 116.23,25.86 D27.R2 | v68.28,78.69 66.24,80.72 66.24,87.63 65.43,88.44 C31.T2 | v434.44,191.67 434.85,191.26 434.85,116.48 v435.66,115.67 | v418.19,95.76 416.56,94.13 416.56,92.91 415.75,92.1 415.75,86 410.06,80.31 410.06,69.75 412.5,67.31 412.5,27.89 v408.03,23.42
  Route2 0.203: v434.44,191.67 442.57,199.8 442.57,202.64 AB02.BA1 | v435.66,115.67 435.66,113.23 v418.19,95.76
  Route15 0.203: v408.03,23.42 388.93,23.42 366.57,1.07 277.98,1.07 276.76,2.29 141.02,2.29 122.73,20.57 119.08,20.57 117.86,21.79 117.86,23.01 116.23,24.64 D27.R2
  Bottom 0.203: v121.11,70.16 112.17,79.1 70.31,79.1 69.9,78.69 v68.28,78.69
AC10\  (via drill 0.61)
  Top 0.203: v438.51,143.71 438.51,198.58 439.32,199.39 AB02.BB1
  Route2 0.203: v318.62,98.6 318.62,99.01 326.75,107.14 326.75,108.36 327.15,108.76 328.37,108.76 v361.7,142.09 | v451.92,125.02 436.07,140.87 438.51,143.31 v438.51,143.71
  Bottom 0.203: v318.62,98.6 316.99,96.98 305.21,96.98 303.99,98.2 C13.P1 | v361.7,142.09 362.1,142.49 384.05,142.49 384.86,143.31 388.11,143.31 388.93,142.49 437.29,142.49 v438.51,143.71 | v451.92,125.02 454.36,122.58 455.17,122.58 455.17,118.11 C01.H1
AC11  (via drill 0.61)
  Top 0.203: v398.68,95.76 399.9,94.54 399.9,85.19 399.49,84.78 399.49,79.91 402.74,76.66 402.74,67.31 v397.87,62.43
  Route2 0.203: v398.68,95.76 425.91,122.99 425.91,127.86 433.22,135.18 433.22,142.09 438.51,147.37 438.51,150.22 447.85,159.56 447.85,191.67 453.14,196.95 439.32,210.77 439.32,218.49 AB02.AV1 | v397.87,62.43 393.8,58.37 392.18,58.37 358.04,24.23 352.35,24.23 351.94,23.83 347.07,23.83 346.66,23.42 345.03,23.42 332.84,11.23 329.18,11.23 326.75,8.79 321.46,8.79 318.21,5.54 316.18,5.54 315.77,5.13 299.92,5.13 299.52,4.72 248.72,4.72 246.69,2.69 245.06,2.69 244.65,2.29 141.02,2.29 120.29,23.01 119.48,22.2 D27.S2
  Route15 0.203: D27.S2 119.48,22.61 122.73,22.61 125.98,25.86 123.95,27.89 123.95,29.52 126.39,31.95 76.4,81.94 76.4,83.97 75.18,85.19 C31.U1
AC11\  (via drill 0.61)
  Top 0.203: v449.48,121.36 449.48,120.95 451.92,120.95 C01.F1 | v442.16,128.68 435.25,135.59 435.25,201.83 433.63,203.45 433.63,218.49 AB02.AV2
  Route2 0.203: C13.R1 300.74,95.35 304.39,95.35 305.61,96.57 311.71,96.57 329.18,114.05 329.18,114.86 338.94,124.61 340.16,124.61 356.01,140.46 357.23,140.46 400.71,183.95 400.71,184.35 423.47,207.11 423.47,209.14 432.82,218.49 AB02.AV2
  Bottom 0.203: v449.48,121.36 v442.16,128.68
AC\_ENABLE  (via drill 0.61)
  Top 0.203: v361.29,232.31 361.7,232.72 361.7,235.56 361.29,235.97 361.29,238 362.92,239.62 362.92,243.28 363.32,243.69 A08.L1 | v377.14,230.28 377.55,229.87 377.55,204.27 377.95,203.86 377.95,180.29 v377.14,179.48
  Bottom 0.203: 373.07,182.32 381.2,182.32 | 373.07,182.32 371.86,182.32 370.64,181.1 AB07.BJ2 | 381.2,182.32 382.02,181.51 AB06.BJ2 | v361.29,232.31 361.29,230.28 v377.14,230.28 | v377.14,179.48 375.92,179.48 373.07,182.32 | 393.39,182.32 394.61,181.1 AB05.BJ2 | 381.2,182.32 393.39,182.32 | 405.99,182.32 407.21,181.1 AB04.BJ2 | 393.39,182.32 405.99,182.32 | 419.4,182.32 420.22,181.51 AB03.BJ2 | 405.99,182.32 419.4,182.32 | 419.4,182.32 432,182.32 432.82,181.51 AB02.BJ2
AC_CLEAR  (via drill 0.61)
  Route15 0.203: v112.98,217.68 138.18,192.48 138.18,192.07 138.58,191.67 138.99,191.67 185.32,145.34 185.32,143.71 226.77,102.26 227.58,102.26 264.57,65.28 268.63,65.28 v283.67,50.24
  Bottom 0.203: v112.98,217.68 108.92,217.68 99.16,227.43 54.86,227.43 54.46,227.84 50.39,227.84 49.99,228.24 A33.S1 | v283.67,50.24 284.48,49.43 298.7,49.43 299.52,50.24 D13.F1
AC_CLEAR\  (via drill 0.61)
  Top 0.203: v346.66,46.18 347.07,45.77 347.07,41.71 D09.K2
  Bottom 0.203: v346.66,46.18 339.75,46.18 336.5,49.43 305.61,49.43 303.99,47.8 D13.H1
AC_ENABLE  (via drill 0.61)
  Top 0.203: v351.94,240.84 351.94,242.88 351.13,243.69 A09.L1
  Route15 0.203: v351.94,240.84 351.94,240.03 364.54,227.43 364.54,227.03 385.27,206.3 385.67,206.3 386.08,205.89 386.08,205.08 386.49,204.67 388.52,204.67 407.21,185.98 408.84,185.98 410.46,184.35 AB04.BH2
  Bottom 0.203: 384.45,185.57 374.29,185.57 373.48,184.76 AB07.BH2 | 384.45,185.57 385.27,184.76 AB06.BH2 | 384.45,185.57 396.65,185.57 397.87,184.35 AB05.BH2 399.08,184.35 400.3,185.57 412.5,185.57 | 421.84,185.57 423.06,184.35 AB03.BH2 | 412.5,185.57 421.84,185.57 | 412.5,185.57 411.68,184.76 AB04.BH2 | 421.84,185.57 435.25,185.57 436.07,184.76 AB02.BH2
AC_LOAD  (via drill 0.61)
  Top 0.203: v322.27,174.6 321.06,173.38 321.06,150.22 v322.27,149 | v405.18,199.39 403.56,201.02 403.56,220.93 404.37,221.74 AB05.AU1
  Route2 0.203: v405.18,199.39 357.63,151.84 357.63,149.81 B08.V2
  Bottom 0.203: v322.27,174.6 319.84,174.6 B11.L2 | v322.27,149 323.9,147.37 354.79,147.37 356.41,149 B08.V2 | AB02.AU1 442.16,222.15 440.94,220.93 431.6,220.93 430.78,221.74 AB03.AU1 429.56,222.56 428.35,223.77 419.4,223.77 418.19,222.56 AB04.AU1 416.97,221.74 416.15,220.93 406.81,220.93 | AB07.AU1 379.98,221.74 384.45,221.74 385.27,220.93 388.11,220.93 389.33,222.15 391.36,222.15 AB06.AU1 392.58,221.74 393.39,220.93 406.81,220.93 | 406.81,220.93 405.59,222.15 AB05.AU1
ADD\  (via drill 0.61)
  Route2 0.203: v392.58,210.36 395.43,207.52 395.43,204.27 395.02,203.86 395.02,203.05 371.04,179.07 371.04,177.44 370.64,177.04 370.23,177.04 346.25,153.06 346.25,152.65 345.85,152.25 345.44,152.25 335.28,142.09 330.81,142.09 330.4,141.68 330.4,141.28 316.18,127.05 313.33,127.05 C12.D1
  Route15 0.203: v392.58,210.36 387.71,215.24 387.71,216.05 384.45,219.3 384.45,220.93 362.1,243.28 362.1,245.31 360.48,246.94 A08.K2
  Bottom 0.203: A09.K1 354.79,247.34 359.66,247.34 A08.K2
ADD_ACCEPTED\  (via drill 0.61)
  Top 0.203: v229.21,5.94 130.05,5.94 130.05,46.99 129.24,47.8 129.24,49.43 130.05,50.24 130.05,60 123.95,66.09 123.95,92.91 124.77,93.73 v124.77,94.13
  Route2 0.203: v285.7,7.16 311.71,33.17 316.99,33.17 318.21,34.39 319.02,34.39 327.96,43.33 329.59,43.33 330.4,44.15 330.4,44.96 339.34,53.9 340.56,53.9 D10.E1
  Bottom 0.203: v285.7,7.16 285.29,7.57 239.78,7.57 238.15,5.94 v229.21,5.94 | v124.77,94.13 124.36,93.73 121.92,93.73 120.7,94.94 116.64,94.94 C27.R2
ADDER00  (via drill 0.61)
  Top 0.203: v374.29,205.08 374.7,205.49 374.7,258.72 373.48,259.94 AB07.AE2 | v432,266.85 432,252.22 432.82,251.41 AB02.AJ2 | v388.93,267.67 388.93,269.29 AB06.AB1
  Route2 0.203: v366.57,205.08 352.75,191.26 352.75,190.86 351.54,189.64 351.13,189.64 341.78,180.29 341.78,178.26 B10.K1 | AB06.AB1 388.52,269.29 384.05,269.29 377.14,262.38 375.11,262.38 373.48,260.76 AB07.AE2
  Bottom 0.203: v366.57,205.08 v374.29,205.08 | v432,266.85 430.78,268.07 389.33,268.07 v388.93,267.67
ADDER01  (via drill 0.61)
  Top 0.203: v373.89,201.02 375.11,202.23 375.11,255.88 375.92,256.69 AB07.AF1
  Route2 0.203: v373.89,201.02 355.19,182.32 354.38,182.32 343.81,171.75 341.78,171.75 B10.M1 | AB06.AC1 391.36,266.45 390.96,266.45 390.55,266.04 387.3,266.04 380.39,259.13 378.36,259.13 376.73,257.5 AB07.AF1
ADDER02  (via drill 0.61)
  Top 0.203: v373.48,258.72 373.48,254.66 AB07.AH2 | AB05.AB1 401.12,270.51 399.9,271.73 399.9,273.76 398.68,274.98 390.14,274.98 390.14,273.76 386.89,270.51 386.89,261.98 386.08,261.16 AB06.AE2
  Bottom 0.203: v373.48,258.72 373.89,259.13 384.45,259.13 385.27,259.94 AB06.AE2
ADDER03  (via drill 0.61)
  Top 0.203: v388.11,252.22 388.52,252.63 388.52,256.69 AB06.AF1
  Route2 0.203: AB05.AC1 404.37,266.04 399.9,266.04 392.99,259.13 391.36,259.13 389.74,257.5 AB06.AF1
  Bottom 0.203: v388.11,252.22 371.86,252.22 370.64,251 AB07.AJ2
ADDER04
  Top 0.203: AB06.AH2 386.08,254.66 387.71,256.29 387.71,270.51 391.77,274.57 397.05,274.57 397.05,265.23 398.27,264.01 398.27,261.16 AB05.AE2
  Route2 0.203: AB04.AB1 413.71,269.7 410.06,269.7 402.74,262.38 400.71,262.38 399.08,260.76 AB05.AE2
ADDER05
  Route2 0.203: AB06.AJ2 383.24,250.6 386.08,250.6 388.52,248.16 395.83,255.47 399.9,255.47 401.12,256.69 AB05.AF1 402.34,257.5 403.96,259.13 405.59,259.13 412.9,266.45 416.97,266.45 AB04.AC1
ADDER06
  Top 0.203: AB03.AB1 426.72,270.51 425.91,271.32 425.91,275.79 419,282.7 412.5,282.7 412.5,262.79 411.28,261.57 411.28,261.16 AB04.AE2
  Route2 0.203: AB05.AH2 399.08,254.25 403.15,254.25 407.21,258.32 408.84,258.32 410.46,259.94 AB04.AE2
ADDER07
  Route2 0.203: AB05.AJ2 395.83,250.6 399.9,250.6 402.74,247.75 410.46,255.47 412.5,255.47 413.71,256.69 AB04.AF1 414.93,257.5 416.56,259.13 418.19,259.13 425.5,266.45 429.56,266.45 AB03.AC1
ADDER08  (via drill 0.61)
  Top 0.203: v411.28,258.72 411.28,254.66 AB04.AH2
  Route2 0.203: AB02.AB1 439.32,269.29 435.66,269.29 432.41,266.04 431.6,266.04 427.94,262.38 425.91,262.38 424.28,260.76 AB03.AE2
  Bottom 0.203: v411.28,258.72 411.68,259.13 421.84,259.13 423.06,260.35 AB03.AE2
ADDER09  (via drill 0.61)
  Top 0.203: v407.62,255.47 407.62,251.41 AB04.AJ2
  Bottom 0.203: v407.62,255.47 408.03,255.88 425.09,255.88 | 425.09,255.88 426.31,257.1 AB03.AF1 | 425.09,255.88 444.19,255.88 444.19,260.76 443.38,261.57 443.38,266.04 AB02.AC1
ADDER10  (via drill 0.61)
  Top 0.203: v423.88,258.72 423.88,254.66 AB03.AH2
  Route2 0.203: v359.66,208.74 355.19,204.27 355.19,202.23 343.81,190.86 341.78,190.86 B10.E1 | v388.52,215.65 416.97,244.09 416.97,244.91 421.84,249.78 421.84,251.82 423.47,253.44 AB03.AH2
  Bottom 0.203: v359.66,208.74 358.44,209.96 358.44,215.24 362.1,215.24 362.92,216.05 388.11,216.05 v388.52,215.65 | v423.88,258.72 434.85,258.72 436.07,259.94 AB02.AE2
ADDER11  (via drill 0.61)
  Top 0.203: v338.12,206.3 338.12,200.61 B10.B1 | v372.67,206.3 374.29,207.92 374.29,248.97 v373.89,249.38 | v444.19,252.22 444.19,257.1 440.54,257.1 AB02.AF1
  Route2 0.203: v366.57,256.69 375.92,266.04 375.92,269.29 AB07.AB1
  Route15 0.203: v366.57,256.69 366.98,256.69 373.89,249.78 v373.89,249.38
  Bottom 0.203: v338.12,206.3 v372.67,206.3 | v373.89,249.38 418.59,249.38 419.4,250.19 420.22,250.19 AB03.AJ2 421.44,251 422.66,252.22 v444.19,252.22
ADDER_L\  (via drill 0.61)
  Top 0.203: v348.69,167.28 349.1,167.69 349.1,179.07 347.88,180.29 347.88,181.91 v348.69,182.73 | v410.46,282.3 410.46,283.11 392.18,283.11 380.39,271.32 380.39,267.67 379.98,267.26 AB07.AC1 379.58,266.04 380.8,264.82 380.8,257.1 381.61,256.29 381.61,254.25 386.89,248.97 386.89,221.34 v385.27,219.71
  Route2 0.203: v348.69,167.28 349.1,166.88 349.1,164.44 345.03,160.38 344.22,160.38 343.81,159.97 340.56,159.97 332.03,151.44 332.03,149.81 B10.V2 | v385.27,219.71 383.24,217.68 382.83,217.68 371.04,205.89 371.04,203.86 360.88,193.7 360.48,193.7 349.5,182.73 349.1,182.73 v348.69,182.73
  Route15 0.203: v410.46,282.3 434.85,257.91 434.85,255.88 436.07,254.66 AB02.AH2
  Bottom 0.203: v348.69,182.73 342.6,182.73 341.78,183.54 B10.H1
AND  (via drill 0.61)
  Top 0.203: v383.24,170.94 384.05,170.13 v384.05,124.21
  Route15 0.203: v383.24,170.94 366.17,188.01 366.17,188.42 362.51,192.07 361.7,192.07 356.82,196.95 356.41,196.95 346.25,207.11 345.44,207.11 339.75,212.8 339.75,222.15 339.34,222.56 338.94,222.56 328.78,232.72 328.78,234.34 A11.P1
  Bottom 0.203: v384.05,124.21 379.98,124.21 C07.E1
AND\  (via drill 0.61)
  Top 0.203: v347.88,112.83 347.88,116.89 C09.H2
  Route2 0.203: v320.65,112.83 310.08,102.26 306.83,102.26 C12.N2 | v359.66,125.83 358.85,125.83 353.16,120.14 352.35,120.14 351.54,119.33 349.91,119.33 348.29,117.7 C09.H2
  Bottom 0.203: v320.65,112.83 v347.88,112.83 | v359.66,125.83 374.7,125.83 375.51,126.64 C07.D1
AND_ENABLE  (via drill 0.61)
  Top 0.203: v390.14,176.63 390.14,220.52 390.55,220.93 390.55,231.5 393.39,234.34 393.39,268.48 392.58,269.29 392.58,272.54 AB06.AA1
  Bottom 0.203: v390.14,176.63 365.76,176.63 364.13,175.01 B08.L1 | 390.14,271.73 380.8,271.73 379.98,272.54 AB07.AA1 | 390.14,271.73 391.36,272.95 AB06.AA1 | 403.56,271.73 404.37,272.54 AB05.AA1 | 390.14,271.73 403.56,271.73 | 416.15,271.73 416.97,272.54 AB04.AA1 | 403.56,271.73 416.15,271.73 | 428.75,271.73 429.56,272.54 AB03.AA1 | 416.15,271.73 428.75,271.73 | 428.75,271.73 440.94,271.73 442.16,272.95 AB02.AA1
AND_ENABLE\  (via drill 0.61)
  Top 0.203: B08.K1 366.17,178.26 363.73,178.26 363.73,180.29 B08.J1 364.13,181.51 366.17,183.54 B08.H1 366.17,184.76 364.13,186.79 B08.F1 363.32,188.01 362.1,189.23 v362.1,204.67 | v348.69,244.91 349.5,245.72 349.5,253.03 350.32,253.85 350.32,256.69 A09.F1 | v330.4,204.67 330.4,215.65 329.18,216.86 329.18,221.74 A11.U1
  Route2 0.203: v348.69,244.91 328.78,224.99 328.78,222.96 A11.U1
  Bottom 0.203: v362.1,204.67 361.7,205.08 330.81,205.08 v330.4,204.67
B01V1  (via drill 0.61)
  Top 0.203: v113.39,250.19 111.35,248.16 111.35,235.56 106.88,235.56 A28.P2
  Route2 0.203: v292.61,255.88 294.64,255.88 309.68,270.92 309.68,271.32 310.08,271.73 318.21,271.73 321.46,274.98 323.9,274.98 324.71,275.79 362.92,275.79 366.98,279.86 369.42,279.86 v373.89,284.33
  Route15 0.203: v373.89,284.33 377.55,284.33 416.97,244.91 416.97,244.09 431.6,229.46 431.6,217.68 435.25,214.02 435.25,207.11 453.54,188.82 453.54,188.01 453.95,187.6 453.95,151.03 452.73,149.81 B01.V1
  Bottom 0.203: v113.39,250.19 119.08,255.88 125.17,255.88 127.61,258.32 255.22,258.32 257.66,255.88 v292.61,255.88
B_BK  (via drill 0.61)
  Top 0.203: v311.3,240.84 311.3,230.28 310.08,229.06 A12.S2 309.27,227.84 307.64,226.21 v307.64,213.61
  Route2 0.203: v307.64,213.61 307.64,213.21 305.21,210.77 305.21,209.14 285.7,189.64 285.7,189.23 v268.22,171.75
  Route15 0.203: v329.18,106.32 334.06,101.45 334.87,101.45 341.78,94.54 343,94.54 343.81,93.73 347.88,93.73 356.01,85.6 357.23,85.6 v359.66,83.16 | v268.22,171.75 262.94,166.47 263.75,165.66 263.75,162 286.92,138.84 286.92,138.02 301.55,123.39 301.55,122.58 305.21,118.92 305.21,117.7 311.3,111.61 313.33,111.61 318.21,106.73 319.84,106.73 321.46,105.1 C11.M2
  Bottom 0.203: v311.3,240.84 313.33,242.88 323.49,242.88 323.9,242.47 326.75,242.47 328.37,244.09 331.22,244.09 A10.L2 | v329.18,106.32 328.78,105.92 323.09,105.92 322.68,105.51 C11.M2 | v359.66,83.16 361.7,81.13 368.61,81.13 369.42,81.94 C07.V2
B_CA  (via drill 0.61)
  Top 0.203: v335.69,239.22 336.09,239.62 336.09,243.28 v335.69,243.69 | v442.57,50.24 441.35,51.46 441.35,53.9 438.1,57.15 438.1,76.66 438.51,77.06 438.51,80.72 438.1,81.13 438.1,125.02 437.69,125.42 v437.69,129.08
  Route2 0.203: v309.68,239.22 309.68,240.84 A12.M2 | v442.57,50.24 434.85,42.52 434.85,18.54 433.63,17.32 433.63,13.26 D02.V2
  Route15 0.203: v437.69,129.08 437.69,149 387.71,198.98 387.71,200.2 387.3,200.61 386.49,200.61 384.45,202.64 384.45,204.27 v375.92,212.8 | v366.98,214.83 364.54,217.27 363.32,217.27 357.23,223.37 357.23,223.77 356.82,224.18 356.01,224.18 348.29,231.9 347.07,231.9 335.69,243.28 v335.69,243.69
  Bottom 0.203: v309.68,239.22 310.08,239.62 335.28,239.62 v335.69,239.22 | v335.69,243.69 336.09,244.09 337.72,244.09 A10.L1 | v375.92,212.8 374.7,214.02 367.79,214.02 v366.98,214.83
B_EXECUTE  (via drill 0.61)
  Top 0.203: 310.9,251.82 310.9,258.32 309.68,259.54 A12.E2 309.27,261.16 308.05,262.38 308.05,266.45 303.99,266.45 A13.C1 | 310.9,251.82 310.9,244.09 312.12,242.88 312.12,239.22 312.52,238.81 A12.N1 | 330.4,255.07 330.4,258.72 331.62,259.94 331.62,262.79 A10.D2 | 330.4,247.34 330.4,255.07 | 330.4,247.34 330.4,229.46 v330.81,229.06 330.4,229.06 330.4,217.27 331.62,216.05 331.62,201.83 330.4,200.61 330.4,192.89 330.81,192.48 330.81,188.82 331.62,188.01 B10.F2 | 330.4,247.34 v330.81,247.34 | v349.5,185.98 349.5,180.29 349.91,179.88 349.91,176.22 350.72,175.41 B09.L1 351.54,174.19 352.35,173.38 352.35,148.59 349.5,145.75 v349.5,144.53 | v308.86,251.82 310.9,251.82 | 330.4,255.07 v330.81,255.07 | v284.48,125.83 284.48,124.61 C14.E2 | v313.74,143.71 314.15,143.31 314.15,127.46 314.55,127.05 315.77,127.05 315.77,129.49 C12.C1
  Route2 0.203: v330.81,229.06 329.18,229.06 A11.S1
  Route15 0.203: D09.R2 345.03,25.04 349.1,25.04 349.91,24.23 366.17,24.23 377.14,35.2 338.12,74.22 337.72,74.22 324.31,87.63 324.31,89.26 322.27,91.29 C11.S2 321.46,92.1 319.84,93.73 318.62,93.73 308.05,104.29 308.05,105.51 306.43,107.14 C12.L2 305.61,107.95 303.58,109.98 302.36,109.98 287.73,124.61 286.92,124.61 285.7,125.83 284.89,125.83 v284.48,125.83
  Bottom 0.203: A13.E2 297.49,260.76 298.3,261.57 303.99,261.57 304.8,260.76 308.86,260.76 A12.E2 | v330.81,247.34 334.47,247.34 A10.K2 | v349.5,185.98 335.69,185.98 334.47,187.2 332.44,187.2 B10.F2 | v308.86,251.82 309.68,252.63 313.74,252.63 314.15,253.03 314.96,253.03 315.37,252.63 325.12,252.63 327.96,255.47 330.4,255.47 v330.81,255.07 | v284.48,125.83 314.15,125.83 315.77,127.46 315.77,129.49 C12.C1 | v349.5,144.53 348.69,145.34 323.09,145.34 321.46,143.71 v313.74,143.71
B_FETCH  (via drill 0.61)
  Top 0.203: v302.36,238.81 301.55,239.62 301.55,255.47 300.33,256.69 A13.F1 | v343,99.01 342.6,99.42 342.6,109.17 341.38,110.39 C10.K1 | v338.94,111.61 339.34,112.01 339.34,124.61 338.53,125.42 338.53,126.24 C10.D1 | v321.46,42.93 324.31,45.77 324.31,67.31 325.12,68.12 325.12,80.72 324.31,81.53 324.31,93.73 325.12,94.54 C11.R1 325.93,95.76 326.75,96.57 326.75,115.67 325.53,116.89 v325.53,117.3 | v282.04,73.41 282.45,73.81 282.45,93.32 281.23,94.54 C14.R2 | v316.99,156.31 314.55,153.87 314.55,127.86 v314.96,127.86
  Route2 0.203: v351.13,190.45 v338.53,177.85 338.12,177.85 337.72,177.85 336.5,176.63 336.5,175.82 v316.99,156.31 | C11.H1 329.18,117.7 330.81,117.7 336.09,122.99 336.09,124.21 338.12,126.24 C10.D1
  Route15 0.203: v302.36,238.81 350.72,190.45 v351.13,190.45 | v314.96,127.86 v325.53,117.3 | v282.04,73.41 282.04,73 296.67,58.37 297.08,58.37 298.7,56.74 298.7,56.34 308.86,46.18 310.9,46.18 312.12,44.96 D12.J1
  Bottom 0.203: v338.53,177.85 335.69,177.85 B10.K2 | v351.13,190.45 353.57,190.45 B09.E1 | v343,99.01 346.66,99.01 347.07,98.6 C09.P2 | v314.96,127.86 314.55,128.27 305.61,128.27 303.99,129.9 C13.C1 | v325.53,117.3 327.96,117.3 C11.H1 | v338.94,111.61 340.16,111.61 340.56,111.2 C10.K1 | v321.46,42.93 314.55,42.93 313.33,44.15 D12.J1
B_INHIBIT  (via drill 0.61)
  Top 0.203: v218.24,70.97 215.8,73.41 215.8,93.73 187.35,122.17 v187.35,201.83 | A23.A1 175.56,272.54 174.35,271.32 174.35,254.25 171.09,251 171.09,229.46 174.35,226.21 174.35,205.49 175.97,203.86 B23.A1
  Route15 0.203: v218.24,70.97 242.62,46.58 242.62,44.96 D17.J2
  Bottom 0.203: A24.A1 164.19,273.36 165.41,274.57 174.35,274.57 175.56,273.36 A23.A1 | v187.35,201.83 177.6,201.83 | 177.6,201.83 176.78,202.64 B23.A1 | 177.6,201.83 165.41,201.83 164.19,203.05 B24.A1
B_MEM_ENABLE  (via drill 0.61)
  Top 0.203: 218.64,154.28 218.64,128.27 217.83,127.46 C19.D2 | 218.64,154.28 217.83,155.09 B19.T2 | 218.64,154.28 218.64,224.18 217.83,224.99 A19.T2 | D25.N2 141.83,32.36 145.9,32.36 145.9,52.68 145.09,53.49 D25.E2 | v253.19,38.46 253.59,38.86 253.59,48.62 252.78,49.43 252.78,53.49 D17.E1 | A23.E2 169.88,259.54 168.25,257.91 168.25,240.03 167.03,238.81 A23.N2 166.22,237.59 165,236.37 165,209.55 158.5,203.05 158.5,192.48 157.28,191.26 B24.E2 156.46,190.04 155.25,188.82 155.25,169.72 154.43,168.91 B24.N2 153.62,167.69 152.81,166.88 152.81,128.27 153.62,127.46 C24.D2 153.62,126.24 153.62,122.99 v153.21,122.58 152.81,122.58 152.81,59.18 154.03,57.96 D24.D2 | C25.N2 141.02,102.26 139.8,103.48 139.8,127.46 140.61,128.27 144.27,128.27 144.27,124.61 C25.E2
